# Generated by FakeRAM 2.0
VERSION 5.7 ;
BUSBITCHARS "[]" ;
PROPERTYDEFINITIONS
  MACRO width INTEGER ;
  MACRO depth INTEGER ;
  MACRO banks INTEGER ;
END PROPERTYDEFINITIONS
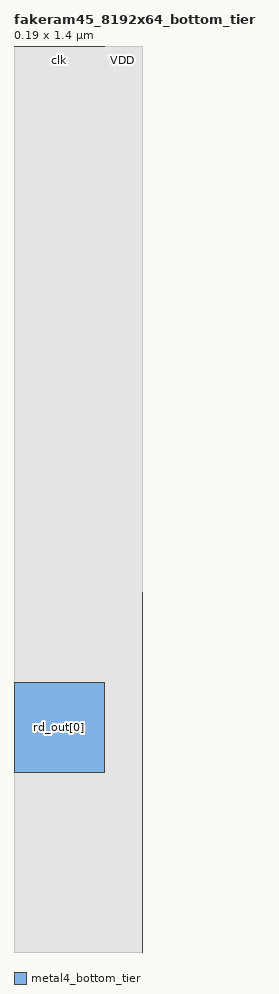
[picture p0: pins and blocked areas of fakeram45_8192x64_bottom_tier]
MACRO fakeram45_8192x64_bottom_tier
  PROPERTY width 64 ;
  PROPERTY depth 8192 ;
  PROPERTY banks 4 ;
  FOREIGN fakeram45_8192x64_bottom_tier 0 0 ;
  SYMMETRY X Y R90 ;
  SIZE 0.19 BY 1.4 ;
  CLASS BLOCK ;
  PIN rd_out[0]
    DIRECTION OUTPUT ;
    USE SIGNAL ;
    SHAPE ABUTMENT ;
    PORT
      LAYER metal4_bottom_tier ;
      RECT 0.000 0.280 0.140 0.420 ;
    END
  END rd_out[0]
  PIN rd_out[1]
    DIRECTION OUTPUT ;
    USE SIGNAL ;
    SHAPE ABUTMENT ;
    PORT
      LAYER metal4_bottom_tier ;
      RECT 0.000 6.160 0.140 6.300 ;
    END
  END rd_out[1]
  PIN rd_out[2]
    DIRECTION OUTPUT ;
    USE SIGNAL ;
    SHAPE ABUTMENT ;
    PORT
      LAYER metal4_bottom_tier ;
      RECT 0.000 12.040 0.140 12.180 ;
    END
  END rd_out[2]
  PIN rd_out[3]
    DIRECTION OUTPUT ;
    USE SIGNAL ;
    SHAPE ABUTMENT ;
    PORT
      LAYER metal4_bottom_tier ;
      RECT 0.000 17.920 0.140 18.060 ;
    END
  END rd_out[3]
  PIN rd_out[4]
    DIRECTION OUTPUT ;
    USE SIGNAL ;
    SHAPE ABUTMENT ;
    PORT
      LAYER metal4_bottom_tier ;
      RECT 0.000 23.800 0.140 23.940 ;
    END
  END rd_out[4]
  PIN rd_out[5]
    DIRECTION OUTPUT ;
    USE SIGNAL ;
    SHAPE ABUTMENT ;
    PORT
      LAYER metal4_bottom_tier ;
      RECT 0.000 29.680 0.140 29.820 ;
    END
  END rd_out[5]
  PIN rd_out[6]
    DIRECTION OUTPUT ;
    USE SIGNAL ;
    SHAPE ABUTMENT ;
    PORT
      LAYER metal4_bottom_tier ;
      RECT 0.000 35.560 0.140 35.700 ;
    END
  END rd_out[6]
  PIN rd_out[7]
    DIRECTION OUTPUT ;
    USE SIGNAL ;
    SHAPE ABUTMENT ;
    PORT
      LAYER metal4_bottom_tier ;
      RECT 0.000 41.440 0.140 41.580 ;
    END
  END rd_out[7]
  PIN rd_out[8]
    DIRECTION OUTPUT ;
    USE SIGNAL ;
    SHAPE ABUTMENT ;
    PORT
      LAYER metal4_bottom_tier ;
      RECT 0.000 47.320 0.140 47.460 ;
    END
  END rd_out[8]
  PIN rd_out[9]
    DIRECTION OUTPUT ;
    USE SIGNAL ;
    SHAPE ABUTMENT ;
    PORT
      LAYER metal4_bottom_tier ;
      RECT 0.000 53.200 0.140 53.340 ;
    END
  END rd_out[9]
  PIN rd_out[10]
    DIRECTION OUTPUT ;
    USE SIGNAL ;
    SHAPE ABUTMENT ;
    PORT
      LAYER metal4_bottom_tier ;
      RECT 0.000 59.080 0.140 59.220 ;
    END
  END rd_out[10]
  PIN rd_out[11]
    DIRECTION OUTPUT ;
    USE SIGNAL ;
    SHAPE ABUTMENT ;
    PORT
      LAYER metal4_bottom_tier ;
      RECT 0.000 64.960 0.140 65.100 ;
    END
  END rd_out[11]
  PIN rd_out[12]
    DIRECTION OUTPUT ;
    USE SIGNAL ;
    SHAPE ABUTMENT ;
    PORT
      LAYER metal4_bottom_tier ;
      RECT 0.000 70.840 0.140 70.980 ;
    END
  END rd_out[12]
  PIN rd_out[13]
    DIRECTION OUTPUT ;
    USE SIGNAL ;
    SHAPE ABUTMENT ;
    PORT
      LAYER metal4_bottom_tier ;
      RECT 0.000 76.720 0.140 76.860 ;
    END
  END rd_out[13]
  PIN rd_out[14]
    DIRECTION OUTPUT ;
    USE SIGNAL ;
    SHAPE ABUTMENT ;
    PORT
      LAYER metal4_bottom_tier ;
      RECT 0.000 82.600 0.140 82.740 ;
    END
  END rd_out[14]
  PIN rd_out[15]
    DIRECTION OUTPUT ;
    USE SIGNAL ;
    SHAPE ABUTMENT ;
    PORT
      LAYER metal4_bottom_tier ;
      RECT 0.000 88.480 0.140 88.620 ;
    END
  END rd_out[15]
  PIN rd_out[16]
    DIRECTION OUTPUT ;
    USE SIGNAL ;
    SHAPE ABUTMENT ;
    PORT
      LAYER metal4_bottom_tier ;
      RECT 0.000 94.360 0.140 94.500 ;
    END
  END rd_out[16]
  PIN rd_out[17]
    DIRECTION OUTPUT ;
    USE SIGNAL ;
    SHAPE ABUTMENT ;
    PORT
      LAYER metal4_bottom_tier ;
      RECT 0.000 100.240 0.140 100.380 ;
    END
  END rd_out[17]
  PIN rd_out[18]
    DIRECTION OUTPUT ;
    USE SIGNAL ;
    SHAPE ABUTMENT ;
    PORT
      LAYER metal4_bottom_tier ;
      RECT 0.000 106.120 0.140 106.260 ;
    END
  END rd_out[18]
  PIN rd_out[19]
    DIRECTION OUTPUT ;
    USE SIGNAL ;
    SHAPE ABUTMENT ;
    PORT
      LAYER metal4_bottom_tier ;
      RECT 0.000 112.000 0.140 112.140 ;
    END
  END rd_out[19]
  PIN rd_out[20]
    DIRECTION OUTPUT ;
    USE SIGNAL ;
    SHAPE ABUTMENT ;
    PORT
      LAYER metal4_bottom_tier ;
      RECT 0.000 117.880 0.140 118.020 ;
    END
  END rd_out[20]
  PIN rd_out[21]
    DIRECTION OUTPUT ;
    USE SIGNAL ;
    SHAPE ABUTMENT ;
    PORT
      LAYER metal4_bottom_tier ;
      RECT 0.000 123.760 0.140 123.900 ;
    END
  END rd_out[21]
  PIN rd_out[22]
    DIRECTION OUTPUT ;
    USE SIGNAL ;
    SHAPE ABUTMENT ;
    PORT
      LAYER metal4_bottom_tier ;
      RECT 0.000 129.640 0.140 129.780 ;
    END
  END rd_out[22]
  PIN rd_out[23]
    DIRECTION OUTPUT ;
    USE SIGNAL ;
    SHAPE ABUTMENT ;
    PORT
      LAYER metal4_bottom_tier ;
      RECT 0.000 135.520 0.140 135.660 ;
    END
  END rd_out[23]
  PIN rd_out[24]
    DIRECTION OUTPUT ;
    USE SIGNAL ;
    SHAPE ABUTMENT ;
    PORT
      LAYER metal4_bottom_tier ;
      RECT 0.000 141.400 0.140 141.540 ;
    END
  END rd_out[24]
  PIN rd_out[25]
    DIRECTION OUTPUT ;
    USE SIGNAL ;
    SHAPE ABUTMENT ;
    PORT
      LAYER metal4_bottom_tier ;
      RECT 0.000 147.280 0.140 147.420 ;
    END
  END rd_out[25]
  PIN rd_out[26]
    DIRECTION OUTPUT ;
    USE SIGNAL ;
    SHAPE ABUTMENT ;
    PORT
      LAYER metal4_bottom_tier ;
      RECT 0.000 153.160 0.140 153.300 ;
    END
  END rd_out[26]
  PIN rd_out[27]
    DIRECTION OUTPUT ;
    USE SIGNAL ;
    SHAPE ABUTMENT ;
    PORT
      LAYER metal4_bottom_tier ;
      RECT 0.000 159.040 0.140 159.180 ;
    END
  END rd_out[27]
  PIN rd_out[28]
    DIRECTION OUTPUT ;
    USE SIGNAL ;
    SHAPE ABUTMENT ;
    PORT
      LAYER metal4_bottom_tier ;
      RECT 0.000 164.920 0.140 165.060 ;
    END
  END rd_out[28]
  PIN rd_out[29]
    DIRECTION OUTPUT ;
    USE SIGNAL ;
    SHAPE ABUTMENT ;
    PORT
      LAYER metal4_bottom_tier ;
      RECT 0.000 170.800 0.140 170.940 ;
    END
  END rd_out[29]
  PIN rd_out[30]
    DIRECTION OUTPUT ;
    USE SIGNAL ;
    SHAPE ABUTMENT ;
    PORT
      LAYER metal4_bottom_tier ;
      RECT 0.000 176.680 0.140 176.820 ;
    END
  END rd_out[30]
  PIN rd_out[31]
    DIRECTION OUTPUT ;
    USE SIGNAL ;
    SHAPE ABUTMENT ;
    PORT
      LAYER metal4_bottom_tier ;
      RECT 0.000 182.560 0.140 182.700 ;
    END
  END rd_out[31]
  PIN rd_out[32]
    DIRECTION OUTPUT ;
    USE SIGNAL ;
    SHAPE ABUTMENT ;
    PORT
      LAYER metal4_bottom_tier ;
      RECT 0.000 188.440 0.140 188.580 ;
    END
  END rd_out[32]
  PIN rd_out[33]
    DIRECTION OUTPUT ;
    USE SIGNAL ;
    SHAPE ABUTMENT ;
    PORT
      LAYER metal4_bottom_tier ;
      RECT 0.000 194.320 0.140 194.460 ;
    END
  END rd_out[33]
  PIN rd_out[34]
    DIRECTION OUTPUT ;
    USE SIGNAL ;
    SHAPE ABUTMENT ;
    PORT
      LAYER metal4_bottom_tier ;
      RECT 0.000 200.200 0.140 200.340 ;
    END
  END rd_out[34]
  PIN rd_out[35]
    DIRECTION OUTPUT ;
    USE SIGNAL ;
    SHAPE ABUTMENT ;
    PORT
      LAYER metal4_bottom_tier ;
      RECT 0.000 206.080 0.140 206.220 ;
    END
  END rd_out[35]
  PIN rd_out[36]
    DIRECTION OUTPUT ;
    USE SIGNAL ;
    SHAPE ABUTMENT ;
    PORT
      LAYER metal4_bottom_tier ;
      RECT 0.000 211.960 0.140 212.100 ;
    END
  END rd_out[36]
  PIN rd_out[37]
    DIRECTION OUTPUT ;
    USE SIGNAL ;
    SHAPE ABUTMENT ;
    PORT
      LAYER metal4_bottom_tier ;
      RECT 0.000 217.840 0.140 217.980 ;
    END
  END rd_out[37]
  PIN rd_out[38]
    DIRECTION OUTPUT ;
    USE SIGNAL ;
    SHAPE ABUTMENT ;
    PORT
      LAYER metal4_bottom_tier ;
      RECT 0.000 223.720 0.140 223.860 ;
    END
  END rd_out[38]
  PIN rd_out[39]
    DIRECTION OUTPUT ;
    USE SIGNAL ;
    SHAPE ABUTMENT ;
    PORT
      LAYER metal4_bottom_tier ;
      RECT 0.000 229.600 0.140 229.740 ;
    END
  END rd_out[39]
  PIN rd_out[40]
    DIRECTION OUTPUT ;
    USE SIGNAL ;
    SHAPE ABUTMENT ;
    PORT
      LAYER metal4_bottom_tier ;
      RECT 0.000 235.480 0.140 235.620 ;
    END
  END rd_out[40]
  PIN rd_out[41]
    DIRECTION OUTPUT ;
    USE SIGNAL ;
    SHAPE ABUTMENT ;
    PORT
      LAYER metal4_bottom_tier ;
      RECT 0.000 241.360 0.140 241.500 ;
    END
  END rd_out[41]
  PIN rd_out[42]
    DIRECTION OUTPUT ;
    USE SIGNAL ;
    SHAPE ABUTMENT ;
    PORT
      LAYER metal4_bottom_tier ;
      RECT 0.000 247.240 0.140 247.380 ;
    END
  END rd_out[42]
  PIN rd_out[43]
    DIRECTION OUTPUT ;
    USE SIGNAL ;
    SHAPE ABUTMENT ;
    PORT
      LAYER metal4_bottom_tier ;
      RECT 0.000 253.120 0.140 253.260 ;
    END
  END rd_out[43]
  PIN rd_out[44]
    DIRECTION OUTPUT ;
    USE SIGNAL ;
    SHAPE ABUTMENT ;
    PORT
      LAYER metal4_bottom_tier ;
      RECT 0.000 259.000 0.140 259.140 ;
    END
  END rd_out[44]
  PIN rd_out[45]
    DIRECTION OUTPUT ;
    USE SIGNAL ;
    SHAPE ABUTMENT ;
    PORT
      LAYER metal4_bottom_tier ;
      RECT 0.000 264.880 0.140 265.020 ;
    END
  END rd_out[45]
  PIN rd_out[46]
    DIRECTION OUTPUT ;
    USE SIGNAL ;
    SHAPE ABUTMENT ;
    PORT
      LAYER metal4_bottom_tier ;
      RECT 0.000 270.760 0.140 270.900 ;
    END
  END rd_out[46]
  PIN rd_out[47]
    DIRECTION OUTPUT ;
    USE SIGNAL ;
    SHAPE ABUTMENT ;
    PORT
      LAYER metal4_bottom_tier ;
      RECT 0.000 276.640 0.140 276.780 ;
    END
  END rd_out[47]
  PIN rd_out[48]
    DIRECTION OUTPUT ;
    USE SIGNAL ;
    SHAPE ABUTMENT ;
    PORT
      LAYER metal4_bottom_tier ;
      RECT 0.000 282.520 0.140 282.660 ;
    END
  END rd_out[48]
  PIN rd_out[49]
    DIRECTION OUTPUT ;
    USE SIGNAL ;
    SHAPE ABUTMENT ;
    PORT
      LAYER metal4_bottom_tier ;
      RECT 0.000 288.400 0.140 288.540 ;
    END
  END rd_out[49]
  PIN rd_out[50]
    DIRECTION OUTPUT ;
    USE SIGNAL ;
    SHAPE ABUTMENT ;
    PORT
      LAYER metal4_bottom_tier ;
      RECT 0.000 294.280 0.140 294.420 ;
    END
  END rd_out[50]
  PIN rd_out[51]
    DIRECTION OUTPUT ;
    USE SIGNAL ;
    SHAPE ABUTMENT ;
    PORT
      LAYER metal4_bottom_tier ;
      RECT 0.000 300.160 0.140 300.300 ;
    END
  END rd_out[51]
  PIN rd_out[52]
    DIRECTION OUTPUT ;
    USE SIGNAL ;
    SHAPE ABUTMENT ;
    PORT
      LAYER metal4_bottom_tier ;
      RECT 0.000 306.040 0.140 306.180 ;
    END
  END rd_out[52]
  PIN rd_out[53]
    DIRECTION OUTPUT ;
    USE SIGNAL ;
    SHAPE ABUTMENT ;
    PORT
      LAYER metal4_bottom_tier ;
      RECT 0.000 311.920 0.140 312.060 ;
    END
  END rd_out[53]
  PIN rd_out[54]
    DIRECTION OUTPUT ;
    USE SIGNAL ;
    SHAPE ABUTMENT ;
    PORT
      LAYER metal4_bottom_tier ;
      RECT 0.000 317.800 0.140 317.940 ;
    END
  END rd_out[54]
  PIN rd_out[55]
    DIRECTION OUTPUT ;
    USE SIGNAL ;
    SHAPE ABUTMENT ;
    PORT
      LAYER metal4_bottom_tier ;
      RECT 0.000 323.680 0.140 323.820 ;
    END
  END rd_out[55]
  PIN rd_out[56]
    DIRECTION OUTPUT ;
    USE SIGNAL ;
    SHAPE ABUTMENT ;
    PORT
      LAYER metal4_bottom_tier ;
      RECT 0.000 329.560 0.140 329.700 ;
    END
  END rd_out[56]
  PIN rd_out[57]
    DIRECTION OUTPUT ;
    USE SIGNAL ;
    SHAPE ABUTMENT ;
    PORT
      LAYER metal4_bottom_tier ;
      RECT 0.000 335.440 0.140 335.580 ;
    END
  END rd_out[57]
  PIN rd_out[58]
    DIRECTION OUTPUT ;
    USE SIGNAL ;
    SHAPE ABUTMENT ;
    PORT
      LAYER metal4_bottom_tier ;
      RECT 0.000 341.320 0.140 341.460 ;
    END
  END rd_out[58]
  PIN rd_out[59]
    DIRECTION OUTPUT ;
    USE SIGNAL ;
    SHAPE ABUTMENT ;
    PORT
      LAYER metal4_bottom_tier ;
      RECT 0.000 347.200 0.140 347.340 ;
    END
  END rd_out[59]
  PIN rd_out[60]
    DIRECTION OUTPUT ;
    USE SIGNAL ;
    SHAPE ABUTMENT ;
    PORT
      LAYER metal4_bottom_tier ;
      RECT 0.000 353.080 0.140 353.220 ;
    END
  END rd_out[60]
  PIN rd_out[61]
    DIRECTION OUTPUT ;
    USE SIGNAL ;
    SHAPE ABUTMENT ;
    PORT
      LAYER metal4_bottom_tier ;
      RECT 0.000 358.960 0.140 359.100 ;
    END
  END rd_out[61]
  PIN rd_out[62]
    DIRECTION OUTPUT ;
    USE SIGNAL ;
    SHAPE ABUTMENT ;
    PORT
      LAYER metal4_bottom_tier ;
      RECT 0.000 364.840 0.140 364.980 ;
    END
  END rd_out[62]
  PIN rd_out[63]
    DIRECTION OUTPUT ;
    USE SIGNAL ;
    SHAPE ABUTMENT ;
    PORT
      LAYER metal4_bottom_tier ;
      RECT 0.000 370.720 0.140 370.860 ;
    END
  END rd_out[63]
  PIN wd_in[0]
    DIRECTION INPUT ;
    USE SIGNAL ;
    SHAPE ABUTMENT ;
    PORT
      LAYER metal4_bottom_tier ;
      RECT 0.000 378.280 0.140 378.420 ;
    END
  END wd_in[0]
  PIN wd_in[1]
    DIRECTION INPUT ;
    USE SIGNAL ;
    SHAPE ABUTMENT ;
    PORT
      LAYER metal4_bottom_tier ;
      RECT 0.000 384.160 0.140 384.300 ;
    END
  END wd_in[1]
  PIN wd_in[2]
    DIRECTION INPUT ;
    USE SIGNAL ;
    SHAPE ABUTMENT ;
    PORT
      LAYER metal4_bottom_tier ;
      RECT 0.000 390.040 0.140 390.180 ;
    END
  END wd_in[2]
  PIN wd_in[3]
    DIRECTION INPUT ;
    USE SIGNAL ;
    SHAPE ABUTMENT ;
    PORT
      LAYER metal4_bottom_tier ;
      RECT 0.000 395.920 0.140 396.060 ;
    END
  END wd_in[3]
  PIN wd_in[4]
    DIRECTION INPUT ;
    USE SIGNAL ;
    SHAPE ABUTMENT ;
    PORT
      LAYER metal4_bottom_tier ;
      RECT 0.000 401.800 0.140 401.940 ;
    END
  END wd_in[4]
  PIN wd_in[5]
    DIRECTION INPUT ;
    USE SIGNAL ;
    SHAPE ABUTMENT ;
    PORT
      LAYER metal4_bottom_tier ;
      RECT 0.000 407.680 0.140 407.820 ;
    END
  END wd_in[5]
  PIN wd_in[6]
    DIRECTION INPUT ;
    USE SIGNAL ;
    SHAPE ABUTMENT ;
    PORT
      LAYER metal4_bottom_tier ;
      RECT 0.000 413.560 0.140 413.700 ;
    END
  END wd_in[6]
  PIN wd_in[7]
    DIRECTION INPUT ;
    USE SIGNAL ;
    SHAPE ABUTMENT ;
    PORT
      LAYER metal4_bottom_tier ;
      RECT 0.000 419.440 0.140 419.580 ;
    END
  END wd_in[7]
  PIN wd_in[8]
    DIRECTION INPUT ;
    USE SIGNAL ;
    SHAPE ABUTMENT ;
    PORT
      LAYER metal4_bottom_tier ;
      RECT 0.000 425.320 0.140 425.460 ;
    END
  END wd_in[8]
  PIN wd_in[9]
    DIRECTION INPUT ;
    USE SIGNAL ;
    SHAPE ABUTMENT ;
    PORT
      LAYER metal4_bottom_tier ;
      RECT 0.000 431.200 0.140 431.340 ;
    END
  END wd_in[9]
  PIN wd_in[10]
    DIRECTION INPUT ;
    USE SIGNAL ;
    SHAPE ABUTMENT ;
    PORT
      LAYER metal4_bottom_tier ;
      RECT 0.000 437.080 0.140 437.220 ;
    END
  END wd_in[10]
  PIN wd_in[11]
    DIRECTION INPUT ;
    USE SIGNAL ;
    SHAPE ABUTMENT ;
    PORT
      LAYER metal4_bottom_tier ;
      RECT 0.000 442.960 0.140 443.100 ;
    END
  END wd_in[11]
  PIN wd_in[12]
    DIRECTION INPUT ;
    USE SIGNAL ;
    SHAPE ABUTMENT ;
    PORT
      LAYER metal4_bottom_tier ;
      RECT 0.000 448.840 0.140 448.980 ;
    END
  END wd_in[12]
  PIN wd_in[13]
    DIRECTION INPUT ;
    USE SIGNAL ;
    SHAPE ABUTMENT ;
    PORT
      LAYER metal4_bottom_tier ;
      RECT 0.000 454.720 0.140 454.860 ;
    END
  END wd_in[13]
  PIN wd_in[14]
    DIRECTION INPUT ;
    USE SIGNAL ;
    SHAPE ABUTMENT ;
    PORT
      LAYER metal4_bottom_tier ;
      RECT 0.000 460.600 0.140 460.740 ;
    END
  END wd_in[14]
  PIN wd_in[15]
    DIRECTION INPUT ;
    USE SIGNAL ;
    SHAPE ABUTMENT ;
    PORT
      LAYER metal4_bottom_tier ;
      RECT 0.000 466.480 0.140 466.620 ;
    END
  END wd_in[15]
  PIN wd_in[16]
    DIRECTION INPUT ;
    USE SIGNAL ;
    SHAPE ABUTMENT ;
    PORT
      LAYER metal4_bottom_tier ;
      RECT 0.000 472.360 0.140 472.500 ;
    END
  END wd_in[16]
  PIN wd_in[17]
    DIRECTION INPUT ;
    USE SIGNAL ;
    SHAPE ABUTMENT ;
    PORT
      LAYER metal4_bottom_tier ;
      RECT 0.000 478.240 0.140 478.380 ;
    END
  END wd_in[17]
  PIN wd_in[18]
    DIRECTION INPUT ;
    USE SIGNAL ;
    SHAPE ABUTMENT ;
    PORT
      LAYER metal4_bottom_tier ;
      RECT 0.000 484.120 0.140 484.260 ;
    END
  END wd_in[18]
  PIN wd_in[19]
    DIRECTION INPUT ;
    USE SIGNAL ;
    SHAPE ABUTMENT ;
    PORT
      LAYER metal4_bottom_tier ;
      RECT 0.000 490.000 0.140 490.140 ;
    END
  END wd_in[19]
  PIN wd_in[20]
    DIRECTION INPUT ;
    USE SIGNAL ;
    SHAPE ABUTMENT ;
    PORT
      LAYER metal4_bottom_tier ;
      RECT 0.000 495.880 0.140 496.020 ;
    END
  END wd_in[20]
  PIN wd_in[21]
    DIRECTION INPUT ;
    USE SIGNAL ;
    SHAPE ABUTMENT ;
    PORT
      LAYER metal4_bottom_tier ;
      RECT 0.000 501.760 0.140 501.900 ;
    END
  END wd_in[21]
  PIN wd_in[22]
    DIRECTION INPUT ;
    USE SIGNAL ;
    SHAPE ABUTMENT ;
    PORT
      LAYER metal4_bottom_tier ;
      RECT 0.000 507.640 0.140 507.780 ;
    END
  END wd_in[22]
  PIN wd_in[23]
    DIRECTION INPUT ;
    USE SIGNAL ;
    SHAPE ABUTMENT ;
    PORT
      LAYER metal4_bottom_tier ;
      RECT 0.000 513.520 0.140 513.660 ;
    END
  END wd_in[23]
  PIN wd_in[24]
    DIRECTION INPUT ;
    USE SIGNAL ;
    SHAPE ABUTMENT ;
    PORT
      LAYER metal4_bottom_tier ;
      RECT 0.000 519.400 0.140 519.540 ;
    END
  END wd_in[24]
  PIN wd_in[25]
    DIRECTION INPUT ;
    USE SIGNAL ;
    SHAPE ABUTMENT ;
    PORT
      LAYER metal4_bottom_tier ;
      RECT 0.000 525.280 0.140 525.420 ;
    END
  END wd_in[25]
  PIN wd_in[26]
    DIRECTION INPUT ;
    USE SIGNAL ;
    SHAPE ABUTMENT ;
    PORT
      LAYER metal4_bottom_tier ;
      RECT 0.000 531.160 0.140 531.300 ;
    END
  END wd_in[26]
  PIN wd_in[27]
    DIRECTION INPUT ;
    USE SIGNAL ;
    SHAPE ABUTMENT ;
    PORT
      LAYER metal4_bottom_tier ;
      RECT 0.000 537.040 0.140 537.180 ;
    END
  END wd_in[27]
  PIN wd_in[28]
    DIRECTION INPUT ;
    USE SIGNAL ;
    SHAPE ABUTMENT ;
    PORT
      LAYER metal4_bottom_tier ;
      RECT 0.000 542.920 0.140 543.060 ;
    END
  END wd_in[28]
  PIN wd_in[29]
    DIRECTION INPUT ;
    USE SIGNAL ;
    SHAPE ABUTMENT ;
    PORT
      LAYER metal4_bottom_tier ;
      RECT 0.000 548.800 0.140 548.940 ;
    END
  END wd_in[29]
  PIN wd_in[30]
    DIRECTION INPUT ;
    USE SIGNAL ;
    SHAPE ABUTMENT ;
    PORT
      LAYER metal4_bottom_tier ;
      RECT 0.000 554.680 0.140 554.820 ;
    END
  END wd_in[30]
  PIN wd_in[31]
    DIRECTION INPUT ;
    USE SIGNAL ;
    SHAPE ABUTMENT ;
    PORT
      LAYER metal4_bottom_tier ;
      RECT 0.000 560.560 0.140 560.700 ;
    END
  END wd_in[31]
  PIN wd_in[32]
    DIRECTION INPUT ;
    USE SIGNAL ;
    SHAPE ABUTMENT ;
    PORT
      LAYER metal4_bottom_tier ;
      RECT 0.000 566.440 0.140 566.580 ;
    END
  END wd_in[32]
  PIN wd_in[33]
    DIRECTION INPUT ;
    USE SIGNAL ;
    SHAPE ABUTMENT ;
    PORT
      LAYER metal4_bottom_tier ;
      RECT 0.000 572.320 0.140 572.460 ;
    END
  END wd_in[33]
  PIN wd_in[34]
    DIRECTION INPUT ;
    USE SIGNAL ;
    SHAPE ABUTMENT ;
    PORT
      LAYER metal4_bottom_tier ;
      RECT 0.000 578.200 0.140 578.340 ;
    END
  END wd_in[34]
  PIN wd_in[35]
    DIRECTION INPUT ;
    USE SIGNAL ;
    SHAPE ABUTMENT ;
    PORT
      LAYER metal4_bottom_tier ;
      RECT 0.000 584.080 0.140 584.220 ;
    END
  END wd_in[35]
  PIN wd_in[36]
    DIRECTION INPUT ;
    USE SIGNAL ;
    SHAPE ABUTMENT ;
    PORT
      LAYER metal4_bottom_tier ;
      RECT 0.000 589.960 0.140 590.100 ;
    END
  END wd_in[36]
  PIN wd_in[37]
    DIRECTION INPUT ;
    USE SIGNAL ;
    SHAPE ABUTMENT ;
    PORT
      LAYER metal4_bottom_tier ;
      RECT 0.000 595.840 0.140 595.980 ;
    END
  END wd_in[37]
  PIN wd_in[38]
    DIRECTION INPUT ;
    USE SIGNAL ;
    SHAPE ABUTMENT ;
    PORT
      LAYER metal4_bottom_tier ;
      RECT 0.000 601.720 0.140 601.860 ;
    END
  END wd_in[38]
  PIN wd_in[39]
    DIRECTION INPUT ;
    USE SIGNAL ;
    SHAPE ABUTMENT ;
    PORT
      LAYER metal4_bottom_tier ;
      RECT 0.000 607.600 0.140 607.740 ;
    END
  END wd_in[39]
  PIN wd_in[40]
    DIRECTION INPUT ;
    USE SIGNAL ;
    SHAPE ABUTMENT ;
    PORT
      LAYER metal4_bottom_tier ;
      RECT 0.000 613.480 0.140 613.620 ;
    END
  END wd_in[40]
  PIN wd_in[41]
    DIRECTION INPUT ;
    USE SIGNAL ;
    SHAPE ABUTMENT ;
    PORT
      LAYER metal4_bottom_tier ;
      RECT 0.000 619.360 0.140 619.500 ;
    END
  END wd_in[41]
  PIN wd_in[42]
    DIRECTION INPUT ;
    USE SIGNAL ;
    SHAPE ABUTMENT ;
    PORT
      LAYER metal4_bottom_tier ;
      RECT 0.000 625.240 0.140 625.380 ;
    END
  END wd_in[42]
  PIN wd_in[43]
    DIRECTION INPUT ;
    USE SIGNAL ;
    SHAPE ABUTMENT ;
    PORT
      LAYER metal4_bottom_tier ;
      RECT 0.000 631.120 0.140 631.260 ;
    END
  END wd_in[43]
  PIN wd_in[44]
    DIRECTION INPUT ;
    USE SIGNAL ;
    SHAPE ABUTMENT ;
    PORT
      LAYER metal4_bottom_tier ;
      RECT 0.000 637.000 0.140 637.140 ;
    END
  END wd_in[44]
  PIN wd_in[45]
    DIRECTION INPUT ;
    USE SIGNAL ;
    SHAPE ABUTMENT ;
    PORT
      LAYER metal4_bottom_tier ;
      RECT 0.000 642.880 0.140 643.020 ;
    END
  END wd_in[45]
  PIN wd_in[46]
    DIRECTION INPUT ;
    USE SIGNAL ;
    SHAPE ABUTMENT ;
    PORT
      LAYER metal4_bottom_tier ;
      RECT 0.000 648.760 0.140 648.900 ;
    END
  END wd_in[46]
  PIN wd_in[47]
    DIRECTION INPUT ;
    USE SIGNAL ;
    SHAPE ABUTMENT ;
    PORT
      LAYER metal4_bottom_tier ;
      RECT 0.000 654.640 0.140 654.780 ;
    END
  END wd_in[47]
  PIN wd_in[48]
    DIRECTION INPUT ;
    USE SIGNAL ;
    SHAPE ABUTMENT ;
    PORT
      LAYER metal4_bottom_tier ;
      RECT 0.000 660.520 0.140 660.660 ;
    END
  END wd_in[48]
  PIN wd_in[49]
    DIRECTION INPUT ;
    USE SIGNAL ;
    SHAPE ABUTMENT ;
    PORT
      LAYER metal4_bottom_tier ;
      RECT 0.000 666.400 0.140 666.540 ;
    END
  END wd_in[49]
  PIN wd_in[50]
    DIRECTION INPUT ;
    USE SIGNAL ;
    SHAPE ABUTMENT ;
    PORT
      LAYER metal4_bottom_tier ;
      RECT 0.000 672.280 0.140 672.420 ;
    END
  END wd_in[50]
  PIN wd_in[51]
    DIRECTION INPUT ;
    USE SIGNAL ;
    SHAPE ABUTMENT ;
    PORT
      LAYER metal4_bottom_tier ;
      RECT 0.000 678.160 0.140 678.300 ;
    END
  END wd_in[51]
  PIN wd_in[52]
    DIRECTION INPUT ;
    USE SIGNAL ;
    SHAPE ABUTMENT ;
    PORT
      LAYER metal4_bottom_tier ;
      RECT 0.000 684.040 0.140 684.180 ;
    END
  END wd_in[52]
  PIN wd_in[53]
    DIRECTION INPUT ;
    USE SIGNAL ;
    SHAPE ABUTMENT ;
    PORT
      LAYER metal4_bottom_tier ;
      RECT 0.000 689.920 0.140 690.060 ;
    END
  END wd_in[53]
  PIN wd_in[54]
    DIRECTION INPUT ;
    USE SIGNAL ;
    SHAPE ABUTMENT ;
    PORT
      LAYER metal4_bottom_tier ;
      RECT 0.000 695.800 0.140 695.940 ;
    END
  END wd_in[54]
  PIN wd_in[55]
    DIRECTION INPUT ;
    USE SIGNAL ;
    SHAPE ABUTMENT ;
    PORT
      LAYER metal4_bottom_tier ;
      RECT 0.000 701.680 0.140 701.820 ;
    END
  END wd_in[55]
  PIN wd_in[56]
    DIRECTION INPUT ;
    USE SIGNAL ;
    SHAPE ABUTMENT ;
    PORT
      LAYER metal4_bottom_tier ;
      RECT 0.000 707.560 0.140 707.700 ;
    END
  END wd_in[56]
  PIN wd_in[57]
    DIRECTION INPUT ;
    USE SIGNAL ;
    SHAPE ABUTMENT ;
    PORT
      LAYER metal4_bottom_tier ;
      RECT 0.000 713.440 0.140 713.580 ;
    END
  END wd_in[57]
  PIN wd_in[58]
    DIRECTION INPUT ;
    USE SIGNAL ;
    SHAPE ABUTMENT ;
    PORT
      LAYER metal4_bottom_tier ;
      RECT 0.000 719.320 0.140 719.460 ;
    END
  END wd_in[58]
  PIN wd_in[59]
    DIRECTION INPUT ;
    USE SIGNAL ;
    SHAPE ABUTMENT ;
    PORT
      LAYER metal4_bottom_tier ;
      RECT 0.000 725.200 0.140 725.340 ;
    END
  END wd_in[59]
  PIN wd_in[60]
    DIRECTION INPUT ;
    USE SIGNAL ;
    SHAPE ABUTMENT ;
    PORT
      LAYER metal4_bottom_tier ;
      RECT 0.000 731.080 0.140 731.220 ;
    END
  END wd_in[60]
  PIN wd_in[61]
    DIRECTION INPUT ;
    USE SIGNAL ;
    SHAPE ABUTMENT ;
    PORT
      LAYER metal4_bottom_tier ;
      RECT 0.000 736.960 0.140 737.100 ;
    END
  END wd_in[61]
  PIN wd_in[62]
    DIRECTION INPUT ;
    USE SIGNAL ;
    SHAPE ABUTMENT ;
    PORT
      LAYER metal4_bottom_tier ;
      RECT 0.000 742.840 0.140 742.980 ;
    END
  END wd_in[62]
  PIN wd_in[63]
    DIRECTION INPUT ;
    USE SIGNAL ;
    SHAPE ABUTMENT ;
    PORT
      LAYER metal4_bottom_tier ;
      RECT 0.000 748.720 0.140 748.860 ;
    END
  END wd_in[63]
  PIN addr_in[0]
    DIRECTION INPUT ;
    USE SIGNAL ;
    SHAPE ABUTMENT ;
    PORT
      LAYER metal4_bottom_tier ;
      RECT 0.000 756.280 0.140 756.420 ;
    END
  END addr_in[0]
  PIN addr_in[1]
    DIRECTION INPUT ;
    USE SIGNAL ;
    SHAPE ABUTMENT ;
    PORT
      LAYER metal4_bottom_tier ;
      RECT 0.000 762.160 0.140 762.300 ;
    END
  END addr_in[1]
  PIN addr_in[2]
    DIRECTION INPUT ;
    USE SIGNAL ;
    SHAPE ABUTMENT ;
    PORT
      LAYER metal4_bottom_tier ;
      RECT 0.000 768.040 0.140 768.180 ;
    END
  END addr_in[2]
  PIN addr_in[3]
    DIRECTION INPUT ;
    USE SIGNAL ;
    SHAPE ABUTMENT ;
    PORT
      LAYER metal4_bottom_tier ;
      RECT 0.000 773.920 0.140 774.060 ;
    END
  END addr_in[3]
  PIN addr_in[4]
    DIRECTION INPUT ;
    USE SIGNAL ;
    SHAPE ABUTMENT ;
    PORT
      LAYER metal4_bottom_tier ;
      RECT 0.000 779.800 0.140 779.940 ;
    END
  END addr_in[4]
  PIN addr_in[5]
    DIRECTION INPUT ;
    USE SIGNAL ;
    SHAPE ABUTMENT ;
    PORT
      LAYER metal4_bottom_tier ;
      RECT 0.000 785.680 0.140 785.820 ;
    END
  END addr_in[5]
  PIN addr_in[6]
    DIRECTION INPUT ;
    USE SIGNAL ;
    SHAPE ABUTMENT ;
    PORT
      LAYER metal4_bottom_tier ;
      RECT 0.000 791.560 0.140 791.700 ;
    END
  END addr_in[6]
  PIN addr_in[7]
    DIRECTION INPUT ;
    USE SIGNAL ;
    SHAPE ABUTMENT ;
    PORT
      LAYER metal4_bottom_tier ;
      RECT 0.000 797.440 0.140 797.580 ;
    END
  END addr_in[7]
  PIN addr_in[8]
    DIRECTION INPUT ;
    USE SIGNAL ;
    SHAPE ABUTMENT ;
    PORT
      LAYER metal4_bottom_tier ;
      RECT 0.000 803.320 0.140 803.460 ;
    END
  END addr_in[8]
  PIN addr_in[9]
    DIRECTION INPUT ;
    USE SIGNAL ;
    SHAPE ABUTMENT ;
    PORT
      LAYER metal4_bottom_tier ;
      RECT 0.000 809.200 0.140 809.340 ;
    END
  END addr_in[9]
  PIN addr_in[10]
    DIRECTION INPUT ;
    USE SIGNAL ;
    SHAPE ABUTMENT ;
    PORT
      LAYER metal4_bottom_tier ;
      RECT 0.000 815.080 0.140 815.220 ;
    END
  END addr_in[10]
  PIN addr_in[11]
    DIRECTION INPUT ;
    USE SIGNAL ;
    SHAPE ABUTMENT ;
    PORT
      LAYER metal4_bottom_tier ;
      RECT 0.000 820.960 0.140 821.100 ;
    END
  END addr_in[11]
  PIN addr_in[12]
    DIRECTION INPUT ;
    USE SIGNAL ;
    SHAPE ABUTMENT ;
    PORT
      LAYER metal4_bottom_tier ;
      RECT 0.000 826.840 0.140 826.980 ;
    END
  END addr_in[12]
  PIN w_mask_in[0]
    DIRECTION OUTPUT ;
    USE SIGNAL ;
    SHAPE ABUTMENT ;
    PORT
      LAYER metal4_bottom_tier ;
      RECT 0.000 834.400 0.140 834.540 ;
    END
  END w_mask_in[0]
  PIN w_mask_in[1]
    DIRECTION OUTPUT ;
    USE SIGNAL ;
    SHAPE ABUTMENT ;
    PORT
      LAYER metal4_bottom_tier ;
      RECT 0.000 840.280 0.140 840.420 ;
    END
  END w_mask_in[1]
  PIN w_mask_in[2]
    DIRECTION OUTPUT ;
    USE SIGNAL ;
    SHAPE ABUTMENT ;
    PORT
      LAYER metal4_bottom_tier ;
      RECT 0.000 846.160 0.140 846.300 ;
    END
  END w_mask_in[2]
  PIN w_mask_in[3]
    DIRECTION OUTPUT ;
    USE SIGNAL ;
    SHAPE ABUTMENT ;
    PORT
      LAYER metal4_bottom_tier ;
      RECT 0.000 852.040 0.140 852.180 ;
    END
  END w_mask_in[3]
  PIN w_mask_in[4]
    DIRECTION OUTPUT ;
    USE SIGNAL ;
    SHAPE ABUTMENT ;
    PORT
      LAYER metal4_bottom_tier ;
      RECT 0.000 857.920 0.140 858.060 ;
    END
  END w_mask_in[4]
  PIN w_mask_in[5]
    DIRECTION OUTPUT ;
    USE SIGNAL ;
    SHAPE ABUTMENT ;
    PORT
      LAYER metal4_bottom_tier ;
      RECT 0.000 863.800 0.140 863.940 ;
    END
  END w_mask_in[5]
  PIN w_mask_in[6]
    DIRECTION OUTPUT ;
    USE SIGNAL ;
    SHAPE ABUTMENT ;
    PORT
      LAYER metal4_bottom_tier ;
      RECT 0.000 869.680 0.140 869.820 ;
    END
  END w_mask_in[6]
  PIN w_mask_in[7]
    DIRECTION OUTPUT ;
    USE SIGNAL ;
    SHAPE ABUTMENT ;
    PORT
      LAYER metal4_bottom_tier ;
      RECT 0.000 875.560 0.140 875.700 ;
    END
  END w_mask_in[7]
  PIN w_mask_in[8]
    DIRECTION OUTPUT ;
    USE SIGNAL ;
    SHAPE ABUTMENT ;
    PORT
      LAYER metal4_bottom_tier ;
      RECT 0.000 881.440 0.140 881.580 ;
    END
  END w_mask_in[8]
  PIN w_mask_in[9]
    DIRECTION OUTPUT ;
    USE SIGNAL ;
    SHAPE ABUTMENT ;
    PORT
      LAYER metal4_bottom_tier ;
      RECT 0.000 887.320 0.140 887.460 ;
    END
  END w_mask_in[9]
  PIN w_mask_in[10]
    DIRECTION OUTPUT ;
    USE SIGNAL ;
    SHAPE ABUTMENT ;
    PORT
      LAYER metal4_bottom_tier ;
      RECT 0.000 893.200 0.140 893.340 ;
    END
  END w_mask_in[10]
  PIN w_mask_in[11]
    DIRECTION OUTPUT ;
    USE SIGNAL ;
    SHAPE ABUTMENT ;
    PORT
      LAYER metal4_bottom_tier ;
      RECT 0.000 899.080 0.140 899.220 ;
    END
  END w_mask_in[11]
  PIN w_mask_in[12]
    DIRECTION OUTPUT ;
    USE SIGNAL ;
    SHAPE ABUTMENT ;
    PORT
      LAYER metal4_bottom_tier ;
      RECT 0.000 904.960 0.140 905.100 ;
    END
  END w_mask_in[12]
  PIN w_mask_in[13]
    DIRECTION OUTPUT ;
    USE SIGNAL ;
    SHAPE ABUTMENT ;
    PORT
      LAYER metal4_bottom_tier ;
      RECT 0.000 910.840 0.140 910.980 ;
    END
  END w_mask_in[13]
  PIN w_mask_in[14]
    DIRECTION OUTPUT ;
    USE SIGNAL ;
    SHAPE ABUTMENT ;
    PORT
      LAYER metal4_bottom_tier ;
      RECT 0.000 916.720 0.140 916.860 ;
    END
  END w_mask_in[14]
  PIN w_mask_in[15]
    DIRECTION OUTPUT ;
    USE SIGNAL ;
    SHAPE ABUTMENT ;
    PORT
      LAYER metal4_bottom_tier ;
      RECT 0.000 922.600 0.140 922.740 ;
    END
  END w_mask_in[15]
  PIN w_mask_in[16]
    DIRECTION OUTPUT ;
    USE SIGNAL ;
    SHAPE ABUTMENT ;
    PORT
      LAYER metal4_bottom_tier ;
      RECT 0.000 928.480 0.140 928.620 ;
    END
  END w_mask_in[16]
  PIN w_mask_in[17]
    DIRECTION OUTPUT ;
    USE SIGNAL ;
    SHAPE ABUTMENT ;
    PORT
      LAYER metal4_bottom_tier ;
      RECT 0.000 934.360 0.140 934.500 ;
    END
  END w_mask_in[17]
  PIN w_mask_in[18]
    DIRECTION OUTPUT ;
    USE SIGNAL ;
    SHAPE ABUTMENT ;
    PORT
      LAYER metal4_bottom_tier ;
      RECT 0.000 940.240 0.140 940.380 ;
    END
  END w_mask_in[18]
  PIN w_mask_in[19]
    DIRECTION OUTPUT ;
    USE SIGNAL ;
    SHAPE ABUTMENT ;
    PORT
      LAYER metal4_bottom_tier ;
      RECT 0.000 946.120 0.140 946.260 ;
    END
  END w_mask_in[19]
  PIN w_mask_in[20]
    DIRECTION OUTPUT ;
    USE SIGNAL ;
    SHAPE ABUTMENT ;
    PORT
      LAYER metal4_bottom_tier ;
      RECT 0.000 952.000 0.140 952.140 ;
    END
  END w_mask_in[20]
  PIN w_mask_in[21]
    DIRECTION OUTPUT ;
    USE SIGNAL ;
    SHAPE ABUTMENT ;
    PORT
      LAYER metal4_bottom_tier ;
      RECT 0.000 957.880 0.140 958.020 ;
    END
  END w_mask_in[21]
  PIN w_mask_in[22]
    DIRECTION OUTPUT ;
    USE SIGNAL ;
    SHAPE ABUTMENT ;
    PORT
      LAYER metal4_bottom_tier ;
      RECT 0.000 963.760 0.140 963.900 ;
    END
  END w_mask_in[22]
  PIN w_mask_in[23]
    DIRECTION OUTPUT ;
    USE SIGNAL ;
    SHAPE ABUTMENT ;
    PORT
      LAYER metal4_bottom_tier ;
      RECT 0.000 969.640 0.140 969.780 ;
    END
  END w_mask_in[23]
  PIN w_mask_in[24]
    DIRECTION OUTPUT ;
    USE SIGNAL ;
    SHAPE ABUTMENT ;
    PORT
      LAYER metal4_bottom_tier ;
      RECT 0.000 975.520 0.140 975.660 ;
    END
  END w_mask_in[24]
  PIN w_mask_in[25]
    DIRECTION OUTPUT ;
    USE SIGNAL ;
    SHAPE ABUTMENT ;
    PORT
      LAYER metal4_bottom_tier ;
      RECT 0.000 981.400 0.140 981.540 ;
    END
  END w_mask_in[25]
  PIN w_mask_in[26]
    DIRECTION OUTPUT ;
    USE SIGNAL ;
    SHAPE ABUTMENT ;
    PORT
      LAYER metal4_bottom_tier ;
      RECT 0.000 987.280 0.140 987.420 ;
    END
  END w_mask_in[26]
  PIN w_mask_in[27]
    DIRECTION OUTPUT ;
    USE SIGNAL ;
    SHAPE ABUTMENT ;
    PORT
      LAYER metal4_bottom_tier ;
      RECT 0.000 993.160 0.140 993.300 ;
    END
  END w_mask_in[27]
  PIN w_mask_in[28]
    DIRECTION OUTPUT ;
    USE SIGNAL ;
    SHAPE ABUTMENT ;
    PORT
      LAYER metal4_bottom_tier ;
      RECT 0.000 999.040 0.140 999.180 ;
    END
  END w_mask_in[28]
  PIN w_mask_in[29]
    DIRECTION OUTPUT ;
    USE SIGNAL ;
    SHAPE ABUTMENT ;
    PORT
      LAYER metal4_bottom_tier ;
      RECT 0.000 1004.920 0.140 1005.060 ;
    END
  END w_mask_in[29]
  PIN w_mask_in[30]
    DIRECTION OUTPUT ;
    USE SIGNAL ;
    SHAPE ABUTMENT ;
    PORT
      LAYER metal4_bottom_tier ;
      RECT 0.000 1010.800 0.140 1010.940 ;
    END
  END w_mask_in[30]
  PIN w_mask_in[31]
    DIRECTION OUTPUT ;
    USE SIGNAL ;
    SHAPE ABUTMENT ;
    PORT
      LAYER metal4_bottom_tier ;
      RECT 0.000 1016.680 0.140 1016.820 ;
    END
  END w_mask_in[31]
  PIN w_mask_in[32]
    DIRECTION OUTPUT ;
    USE SIGNAL ;
    SHAPE ABUTMENT ;
    PORT
      LAYER metal4_bottom_tier ;
      RECT 0.000 1022.560 0.140 1022.700 ;
    END
  END w_mask_in[32]
  PIN w_mask_in[33]
    DIRECTION OUTPUT ;
    USE SIGNAL ;
    SHAPE ABUTMENT ;
    PORT
      LAYER metal4_bottom_tier ;
      RECT 0.000 1028.440 0.140 1028.580 ;
    END
  END w_mask_in[33]
  PIN w_mask_in[34]
    DIRECTION OUTPUT ;
    USE SIGNAL ;
    SHAPE ABUTMENT ;
    PORT
      LAYER metal4_bottom_tier ;
      RECT 0.000 1034.320 0.140 1034.460 ;
    END
  END w_mask_in[34]
  PIN w_mask_in[35]
    DIRECTION OUTPUT ;
    USE SIGNAL ;
    SHAPE ABUTMENT ;
    PORT
      LAYER metal4_bottom_tier ;
      RECT 0.000 1040.200 0.140 1040.340 ;
    END
  END w_mask_in[35]
  PIN w_mask_in[36]
    DIRECTION OUTPUT ;
    USE SIGNAL ;
    SHAPE ABUTMENT ;
    PORT
      LAYER metal4_bottom_tier ;
      RECT 0.000 1046.080 0.140 1046.220 ;
    END
  END w_mask_in[36]
  PIN w_mask_in[37]
    DIRECTION OUTPUT ;
    USE SIGNAL ;
    SHAPE ABUTMENT ;
    PORT
      LAYER metal4_bottom_tier ;
      RECT 0.000 1051.960 0.140 1052.100 ;
    END
  END w_mask_in[37]
  PIN w_mask_in[38]
    DIRECTION OUTPUT ;
    USE SIGNAL ;
    SHAPE ABUTMENT ;
    PORT
      LAYER metal4_bottom_tier ;
      RECT 0.000 1057.840 0.140 1057.980 ;
    END
  END w_mask_in[38]
  PIN w_mask_in[39]
    DIRECTION OUTPUT ;
    USE SIGNAL ;
    SHAPE ABUTMENT ;
    PORT
      LAYER metal4_bottom_tier ;
      RECT 0.000 1063.720 0.140 1063.860 ;
    END
  END w_mask_in[39]
  PIN w_mask_in[40]
    DIRECTION OUTPUT ;
    USE SIGNAL ;
    SHAPE ABUTMENT ;
    PORT
      LAYER metal4_bottom_tier ;
      RECT 0.000 1069.600 0.140 1069.740 ;
    END
  END w_mask_in[40]
  PIN w_mask_in[41]
    DIRECTION OUTPUT ;
    USE SIGNAL ;
    SHAPE ABUTMENT ;
    PORT
      LAYER metal4_bottom_tier ;
      RECT 0.000 1075.480 0.140 1075.620 ;
    END
  END w_mask_in[41]
  PIN w_mask_in[42]
    DIRECTION OUTPUT ;
    USE SIGNAL ;
    SHAPE ABUTMENT ;
    PORT
      LAYER metal4_bottom_tier ;
      RECT 0.000 1081.360 0.140 1081.500 ;
    END
  END w_mask_in[42]
  PIN w_mask_in[43]
    DIRECTION OUTPUT ;
    USE SIGNAL ;
    SHAPE ABUTMENT ;
    PORT
      LAYER metal4_bottom_tier ;
      RECT 0.000 1087.240 0.140 1087.380 ;
    END
  END w_mask_in[43]
  PIN w_mask_in[44]
    DIRECTION OUTPUT ;
    USE SIGNAL ;
    SHAPE ABUTMENT ;
    PORT
      LAYER metal4_bottom_tier ;
      RECT 0.000 1093.120 0.140 1093.260 ;
    END
  END w_mask_in[44]
  PIN w_mask_in[45]
    DIRECTION OUTPUT ;
    USE SIGNAL ;
    SHAPE ABUTMENT ;
    PORT
      LAYER metal4_bottom_tier ;
      RECT 0.000 1099.000 0.140 1099.140 ;
    END
  END w_mask_in[45]
  PIN w_mask_in[46]
    DIRECTION OUTPUT ;
    USE SIGNAL ;
    SHAPE ABUTMENT ;
    PORT
      LAYER metal4_bottom_tier ;
      RECT 0.000 1104.880 0.140 1105.020 ;
    END
  END w_mask_in[46]
  PIN w_mask_in[47]
    DIRECTION OUTPUT ;
    USE SIGNAL ;
    SHAPE ABUTMENT ;
    PORT
      LAYER metal4_bottom_tier ;
      RECT 0.000 1110.760 0.140 1110.900 ;
    END
  END w_mask_in[47]
  PIN w_mask_in[48]
    DIRECTION OUTPUT ;
    USE SIGNAL ;
    SHAPE ABUTMENT ;
    PORT
      LAYER metal4_bottom_tier ;
      RECT 0.000 1116.640 0.140 1116.780 ;
    END
  END w_mask_in[48]
  PIN w_mask_in[49]
    DIRECTION OUTPUT ;
    USE SIGNAL ;
    SHAPE ABUTMENT ;
    PORT
      LAYER metal4_bottom_tier ;
      RECT 0.000 1122.520 0.140 1122.660 ;
    END
  END w_mask_in[49]
  PIN w_mask_in[50]
    DIRECTION OUTPUT ;
    USE SIGNAL ;
    SHAPE ABUTMENT ;
    PORT
      LAYER metal4_bottom_tier ;
      RECT 0.000 1128.400 0.140 1128.540 ;
    END
  END w_mask_in[50]
  PIN w_mask_in[51]
    DIRECTION OUTPUT ;
    USE SIGNAL ;
    SHAPE ABUTMENT ;
    PORT
      LAYER metal4_bottom_tier ;
      RECT 0.000 1134.280 0.140 1134.420 ;
    END
  END w_mask_in[51]
  PIN w_mask_in[52]
    DIRECTION OUTPUT ;
    USE SIGNAL ;
    SHAPE ABUTMENT ;
    PORT
      LAYER metal4_bottom_tier ;
      RECT 0.000 1140.160 0.140 1140.300 ;
    END
  END w_mask_in[52]
  PIN w_mask_in[53]
    DIRECTION OUTPUT ;
    USE SIGNAL ;
    SHAPE ABUTMENT ;
    PORT
      LAYER metal4_bottom_tier ;
      RECT 0.000 1146.040 0.140 1146.180 ;
    END
  END w_mask_in[53]
  PIN w_mask_in[54]
    DIRECTION OUTPUT ;
    USE SIGNAL ;
    SHAPE ABUTMENT ;
    PORT
      LAYER metal4_bottom_tier ;
      RECT 0.000 1151.920 0.140 1152.060 ;
    END
  END w_mask_in[54]
  PIN w_mask_in[55]
    DIRECTION OUTPUT ;
    USE SIGNAL ;
    SHAPE ABUTMENT ;
    PORT
      LAYER metal4_bottom_tier ;
      RECT 0.000 1157.800 0.140 1157.940 ;
    END
  END w_mask_in[55]
  PIN w_mask_in[56]
    DIRECTION OUTPUT ;
    USE SIGNAL ;
    SHAPE ABUTMENT ;
    PORT
      LAYER metal4_bottom_tier ;
      RECT 0.000 1163.680 0.140 1163.820 ;
    END
  END w_mask_in[56]
  PIN w_mask_in[57]
    DIRECTION OUTPUT ;
    USE SIGNAL ;
    SHAPE ABUTMENT ;
    PORT
      LAYER metal4_bottom_tier ;
      RECT 0.000 1169.560 0.140 1169.700 ;
    END
  END w_mask_in[57]
  PIN w_mask_in[58]
    DIRECTION OUTPUT ;
    USE SIGNAL ;
    SHAPE ABUTMENT ;
    PORT
      LAYER metal4_bottom_tier ;
      RECT 0.000 1175.440 0.140 1175.580 ;
    END
  END w_mask_in[58]
  PIN w_mask_in[59]
    DIRECTION OUTPUT ;
    USE SIGNAL ;
    SHAPE ABUTMENT ;
    PORT
      LAYER metal4_bottom_tier ;
      RECT 0.000 1181.320 0.140 1181.460 ;
    END
  END w_mask_in[59]
  PIN w_mask_in[60]
    DIRECTION OUTPUT ;
    USE SIGNAL ;
    SHAPE ABUTMENT ;
    PORT
      LAYER metal4_bottom_tier ;
      RECT 0.000 1187.200 0.140 1187.340 ;
    END
  END w_mask_in[60]
  PIN w_mask_in[61]
    DIRECTION OUTPUT ;
    USE SIGNAL ;
    SHAPE ABUTMENT ;
    PORT
      LAYER metal4_bottom_tier ;
      RECT 0.000 1193.080 0.140 1193.220 ;
    END
  END w_mask_in[61]
  PIN w_mask_in[62]
    DIRECTION OUTPUT ;
    USE SIGNAL ;
    SHAPE ABUTMENT ;
    PORT
      LAYER metal4_bottom_tier ;
      RECT 0.000 1198.960 0.140 1199.100 ;
    END
  END w_mask_in[62]
  PIN w_mask_in[63]
    DIRECTION OUTPUT ;
    USE SIGNAL ;
    SHAPE ABUTMENT ;
    PORT
      LAYER metal4_bottom_tier ;
      RECT 0.000 1204.840 0.140 1204.980 ;
    END
  END w_mask_in[63]
  PIN we_in
    DIRECTION INPUT ;
    USE SIGNAL ;
    SHAPE ABUTMENT ;
    PORT
      LAYER metal4_bottom_tier ;
      RECT 0.000 1212.400 0.140 1212.540 ;
    END
  END we_in
  PIN ce_in
    DIRECTION INPUT ;
    USE SIGNAL ;
    SHAPE ABUTMENT ;
    PORT
      LAYER metal4_bottom_tier ;
      RECT 0.000 1218.280 0.140 1218.420 ;
    END
  END ce_in
  PIN clk
    DIRECTION INPUT ;
    USE SIGNAL ;
    SHAPE ABUTMENT ;
    PORT
      LAYER metal4_bottom_tier ;
      RECT 0.000 1224.160 0.140 1224.300 ;
    END
  END clk
  PIN VSS
    DIRECTION INOUT ;
    USE GROUND ;
    PORT
      LAYER metal4_bottom_tier ;
      RECT 0.280 0.000 208.720 0.560 ;
      RECT 0.280 4.480 208.720 5.040 ;
      RECT 0.280 8.960 208.720 9.520 ;
      RECT 0.280 13.440 208.720 14.000 ;
      RECT 0.280 17.920 208.720 18.480 ;
      RECT 0.280 22.400 208.720 22.960 ;
      RECT 0.280 26.880 208.720 27.440 ;
      RECT 0.280 31.360 208.720 31.920 ;
      RECT 0.280 35.840 208.720 36.400 ;
      RECT 0.280 40.320 208.720 40.880 ;
      RECT 0.280 44.800 208.720 45.360 ;
      RECT 0.280 49.280 208.720 49.840 ;
      RECT 0.280 53.760 208.720 54.320 ;
      RECT 0.280 58.240 208.720 58.800 ;
      RECT 0.280 62.720 208.720 63.280 ;
      RECT 0.280 67.200 208.720 67.760 ;
      RECT 0.280 71.680 208.720 72.240 ;
      RECT 0.280 76.160 208.720 76.720 ;
      RECT 0.280 80.640 208.720 81.200 ;
      RECT 0.280 85.120 208.720 85.680 ;
      RECT 0.280 89.600 208.720 90.160 ;
      RECT 0.280 94.080 208.720 94.640 ;
      RECT 0.280 98.560 208.720 99.120 ;
      RECT 0.280 103.040 208.720 103.600 ;
      RECT 0.280 107.520 208.720 108.080 ;
      RECT 0.280 112.000 208.720 112.560 ;
      RECT 0.280 116.480 208.720 117.040 ;
      RECT 0.280 120.960 208.720 121.520 ;
      RECT 0.280 125.440 208.720 126.000 ;
      RECT 0.280 129.920 208.720 130.480 ;
      RECT 0.280 134.400 208.720 134.960 ;
      RECT 0.280 138.880 208.720 139.440 ;
      RECT 0.280 143.360 208.720 143.920 ;
      RECT 0.280 147.840 208.720 148.400 ;
      RECT 0.280 152.320 208.720 152.880 ;
      RECT 0.280 156.800 208.720 157.360 ;
      RECT 0.280 161.280 208.720 161.840 ;
      RECT 0.280 165.760 208.720 166.320 ;
      RECT 0.280 170.240 208.720 170.800 ;
      RECT 0.280 174.720 208.720 175.280 ;
      RECT 0.280 179.200 208.720 179.760 ;
      RECT 0.280 183.680 208.720 184.240 ;
      RECT 0.280 188.160 208.720 188.720 ;
      RECT 0.280 192.640 208.720 193.200 ;
      RECT 0.280 197.120 208.720 197.680 ;
      RECT 0.280 201.600 208.720 202.160 ;
      RECT 0.280 206.080 208.720 206.640 ;
      RECT 0.280 210.560 208.720 211.120 ;
      RECT 0.280 215.040 208.720 215.600 ;
      RECT 0.280 219.520 208.720 220.080 ;
      RECT 0.280 224.000 208.720 224.560 ;
      RECT 0.280 228.480 208.720 229.040 ;
      RECT 0.280 232.960 208.720 233.520 ;
      RECT 0.280 237.440 208.720 238.000 ;
      RECT 0.280 241.920 208.720 242.480 ;
      RECT 0.280 246.400 208.720 246.960 ;
      RECT 0.280 250.880 208.720 251.440 ;
      RECT 0.280 255.360 208.720 255.920 ;
      RECT 0.280 259.840 208.720 260.400 ;
      RECT 0.280 264.320 208.720 264.880 ;
      RECT 0.280 268.800 208.720 269.360 ;
      RECT 0.280 273.280 208.720 273.840 ;
      RECT 0.280 277.760 208.720 278.320 ;
      RECT 0.280 282.240 208.720 282.800 ;
      RECT 0.280 286.720 208.720 287.280 ;
      RECT 0.280 291.200 208.720 291.760 ;
      RECT 0.280 295.680 208.720 296.240 ;
      RECT 0.280 300.160 208.720 300.720 ;
      RECT 0.280 304.640 208.720 305.200 ;
      RECT 0.280 309.120 208.720 309.680 ;
      RECT 0.280 313.600 208.720 314.160 ;
      RECT 0.280 318.080 208.720 318.640 ;
      RECT 0.280 322.560 208.720 323.120 ;
      RECT 0.280 327.040 208.720 327.600 ;
      RECT 0.280 331.520 208.720 332.080 ;
      RECT 0.280 336.000 208.720 336.560 ;
      RECT 0.280 340.480 208.720 341.040 ;
      RECT 0.280 344.960 208.720 345.520 ;
      RECT 0.280 349.440 208.720 350.000 ;
      RECT 0.280 353.920 208.720 354.480 ;
      RECT 0.280 358.400 208.720 358.960 ;
      RECT 0.280 362.880 208.720 363.440 ;
      RECT 0.280 367.360 208.720 367.920 ;
      RECT 0.280 371.840 208.720 372.400 ;
      RECT 0.280 376.320 208.720 376.880 ;
      RECT 0.280 380.800 208.720 381.360 ;
      RECT 0.280 385.280 208.720 385.840 ;
      RECT 0.280 389.760 208.720 390.320 ;
      RECT 0.280 394.240 208.720 394.800 ;
      RECT 0.280 398.720 208.720 399.280 ;
      RECT 0.280 403.200 208.720 403.760 ;
      RECT 0.280 407.680 208.720 408.240 ;
      RECT 0.280 412.160 208.720 412.720 ;
      RECT 0.280 416.640 208.720 417.200 ;
      RECT 0.280 421.120 208.720 421.680 ;
      RECT 0.280 425.600 208.720 426.160 ;
      RECT 0.280 430.080 208.720 430.640 ;
      RECT 0.280 434.560 208.720 435.120 ;
      RECT 0.280 439.040 208.720 439.600 ;
      RECT 0.280 443.520 208.720 444.080 ;
      RECT 0.280 448.000 208.720 448.560 ;
      RECT 0.280 452.480 208.720 453.040 ;
      RECT 0.280 456.960 208.720 457.520 ;
      RECT 0.280 461.440 208.720 462.000 ;
      RECT 0.280 465.920 208.720 466.480 ;
      RECT 0.280 470.400 208.720 470.960 ;
      RECT 0.280 474.880 208.720 475.440 ;
      RECT 0.280 479.360 208.720 479.920 ;
      RECT 0.280 483.840 208.720 484.400 ;
      RECT 0.280 488.320 208.720 488.880 ;
      RECT 0.280 492.800 208.720 493.360 ;
      RECT 0.280 497.280 208.720 497.840 ;
      RECT 0.280 501.760 208.720 502.320 ;
      RECT 0.280 506.240 208.720 506.800 ;
      RECT 0.280 510.720 208.720 511.280 ;
      RECT 0.280 515.200 208.720 515.760 ;
      RECT 0.280 519.680 208.720 520.240 ;
      RECT 0.280 524.160 208.720 524.720 ;
      RECT 0.280 528.640 208.720 529.200 ;
      RECT 0.280 533.120 208.720 533.680 ;
      RECT 0.280 537.600 208.720 538.160 ;
      RECT 0.280 542.080 208.720 542.640 ;
      RECT 0.280 546.560 208.720 547.120 ;
      RECT 0.280 551.040 208.720 551.600 ;
      RECT 0.280 555.520 208.720 556.080 ;
      RECT 0.280 560.000 208.720 560.560 ;
      RECT 0.280 564.480 208.720 565.040 ;
      RECT 0.280 568.960 208.720 569.520 ;
      RECT 0.280 573.440 208.720 574.000 ;
      RECT 0.280 577.920 208.720 578.480 ;
      RECT 0.280 582.400 208.720 582.960 ;
      RECT 0.280 586.880 208.720 587.440 ;
      RECT 0.280 591.360 208.720 591.920 ;
      RECT 0.280 595.840 208.720 596.400 ;
      RECT 0.280 600.320 208.720 600.880 ;
      RECT 0.280 604.800 208.720 605.360 ;
      RECT 0.280 609.280 208.720 609.840 ;
      RECT 0.280 613.760 208.720 614.320 ;
      RECT 0.280 618.240 208.720 618.800 ;
      RECT 0.280 622.720 208.720 623.280 ;
      RECT 0.280 627.200 208.720 627.760 ;
      RECT 0.280 631.680 208.720 632.240 ;
      RECT 0.280 636.160 208.720 636.720 ;
      RECT 0.280 640.640 208.720 641.200 ;
      RECT 0.280 645.120 208.720 645.680 ;
      RECT 0.280 649.600 208.720 650.160 ;
      RECT 0.280 654.080 208.720 654.640 ;
      RECT 0.280 658.560 208.720 659.120 ;
      RECT 0.280 663.040 208.720 663.600 ;
      RECT 0.280 667.520 208.720 668.080 ;
      RECT 0.280 672.000 208.720 672.560 ;
      RECT 0.280 676.480 208.720 677.040 ;
      RECT 0.280 680.960 208.720 681.520 ;
      RECT 0.280 685.440 208.720 686.000 ;
      RECT 0.280 689.920 208.720 690.480 ;
      RECT 0.280 694.400 208.720 694.960 ;
      RECT 0.280 698.880 208.720 699.440 ;
      RECT 0.280 703.360 208.720 703.920 ;
      RECT 0.280 707.840 208.720 708.400 ;
      RECT 0.280 712.320 208.720 712.880 ;
      RECT 0.280 716.800 208.720 717.360 ;
      RECT 0.280 721.280 208.720 721.840 ;
      RECT 0.280 725.760 208.720 726.320 ;
      RECT 0.280 730.240 208.720 730.800 ;
      RECT 0.280 734.720 208.720 735.280 ;
      RECT 0.280 739.200 208.720 739.760 ;
      RECT 0.280 743.680 208.720 744.240 ;
      RECT 0.280 748.160 208.720 748.720 ;
      RECT 0.280 752.640 208.720 753.200 ;
      RECT 0.280 757.120 208.720 757.680 ;
      RECT 0.280 761.600 208.720 762.160 ;
      RECT 0.280 766.080 208.720 766.640 ;
      RECT 0.280 770.560 208.720 771.120 ;
      RECT 0.280 775.040 208.720 775.600 ;
      RECT 0.280 779.520 208.720 780.080 ;
      RECT 0.280 784.000 208.720 784.560 ;
      RECT 0.280 788.480 208.720 789.040 ;
      RECT 0.280 792.960 208.720 793.520 ;
      RECT 0.280 797.440 208.720 798.000 ;
      RECT 0.280 801.920 208.720 802.480 ;
      RECT 0.280 806.400 208.720 806.960 ;
      RECT 0.280 810.880 208.720 811.440 ;
      RECT 0.280 815.360 208.720 815.920 ;
      RECT 0.280 819.840 208.720 820.400 ;
      RECT 0.280 824.320 208.720 824.880 ;
      RECT 0.280 828.800 208.720 829.360 ;
      RECT 0.280 833.280 208.720 833.840 ;
      RECT 0.280 837.760 208.720 838.320 ;
      RECT 0.280 842.240 208.720 842.800 ;
      RECT 0.280 846.720 208.720 847.280 ;
      RECT 0.280 851.200 208.720 851.760 ;
      RECT 0.280 855.680 208.720 856.240 ;
      RECT 0.280 860.160 208.720 860.720 ;
      RECT 0.280 864.640 208.720 865.200 ;
      RECT 0.280 869.120 208.720 869.680 ;
      RECT 0.280 873.600 208.720 874.160 ;
      RECT 0.280 878.080 208.720 878.640 ;
      RECT 0.280 882.560 208.720 883.120 ;
      RECT 0.280 887.040 208.720 887.600 ;
      RECT 0.280 891.520 208.720 892.080 ;
      RECT 0.280 896.000 208.720 896.560 ;
      RECT 0.280 900.480 208.720 901.040 ;
      RECT 0.280 904.960 208.720 905.520 ;
      RECT 0.280 909.440 208.720 910.000 ;
      RECT 0.280 913.920 208.720 914.480 ;
      RECT 0.280 918.400 208.720 918.960 ;
      RECT 0.280 922.880 208.720 923.440 ;
      RECT 0.280 927.360 208.720 927.920 ;
      RECT 0.280 931.840 208.720 932.400 ;
      RECT 0.280 936.320 208.720 936.880 ;
      RECT 0.280 940.800 208.720 941.360 ;
      RECT 0.280 945.280 208.720 945.840 ;
      RECT 0.280 949.760 208.720 950.320 ;
      RECT 0.280 954.240 208.720 954.800 ;
      RECT 0.280 958.720 208.720 959.280 ;
      RECT 0.280 963.200 208.720 963.760 ;
      RECT 0.280 967.680 208.720 968.240 ;
      RECT 0.280 972.160 208.720 972.720 ;
      RECT 0.280 976.640 208.720 977.200 ;
      RECT 0.280 981.120 208.720 981.680 ;
      RECT 0.280 985.600 208.720 986.160 ;
      RECT 0.280 990.080 208.720 990.640 ;
      RECT 0.280 994.560 208.720 995.120 ;
      RECT 0.280 999.040 208.720 999.600 ;
      RECT 0.280 1003.520 208.720 1004.080 ;
      RECT 0.280 1008.000 208.720 1008.560 ;
      RECT 0.280 1012.480 208.720 1013.040 ;
      RECT 0.280 1016.960 208.720 1017.520 ;
      RECT 0.280 1021.440 208.720 1022.000 ;
      RECT 0.280 1025.920 208.720 1026.480 ;
      RECT 0.280 1030.400 208.720 1030.960 ;
      RECT 0.280 1034.880 208.720 1035.440 ;
      RECT 0.280 1039.360 208.720 1039.920 ;
      RECT 0.280 1043.840 208.720 1044.400 ;
      RECT 0.280 1048.320 208.720 1048.880 ;
      RECT 0.280 1052.800 208.720 1053.360 ;
      RECT 0.280 1057.280 208.720 1057.840 ;
      RECT 0.280 1061.760 208.720 1062.320 ;
      RECT 0.280 1066.240 208.720 1066.800 ;
      RECT 0.280 1070.720 208.720 1071.280 ;
      RECT 0.280 1075.200 208.720 1075.760 ;
      RECT 0.280 1079.680 208.720 1080.240 ;
      RECT 0.280 1084.160 208.720 1084.720 ;
      RECT 0.280 1088.640 208.720 1089.200 ;
      RECT 0.280 1093.120 208.720 1093.680 ;
      RECT 0.280 1097.600 208.720 1098.160 ;
      RECT 0.280 1102.080 208.720 1102.640 ;
      RECT 0.280 1106.560 208.720 1107.120 ;
      RECT 0.280 1111.040 208.720 1111.600 ;
      RECT 0.280 1115.520 208.720 1116.080 ;
      RECT 0.280 1120.000 208.720 1120.560 ;
      RECT 0.280 1124.480 208.720 1125.040 ;
      RECT 0.280 1128.960 208.720 1129.520 ;
      RECT 0.280 1133.440 208.720 1134.000 ;
      RECT 0.280 1137.920 208.720 1138.480 ;
      RECT 0.280 1142.400 208.720 1142.960 ;
      RECT 0.280 1146.880 208.720 1147.440 ;
      RECT 0.280 1151.360 208.720 1151.920 ;
      RECT 0.280 1155.840 208.720 1156.400 ;
      RECT 0.280 1160.320 208.720 1160.880 ;
      RECT 0.280 1164.800 208.720 1165.360 ;
      RECT 0.280 1169.280 208.720 1169.840 ;
      RECT 0.280 1173.760 208.720 1174.320 ;
      RECT 0.280 1178.240 208.720 1178.800 ;
      RECT 0.280 1182.720 208.720 1183.280 ;
      RECT 0.280 1187.200 208.720 1187.760 ;
      RECT 0.280 1191.680 208.720 1192.240 ;
      RECT 0.280 1196.160 208.720 1196.720 ;
      RECT 0.280 1200.640 208.720 1201.200 ;
      RECT 0.280 1205.120 208.720 1205.680 ;
      RECT 0.280 1209.600 208.720 1210.160 ;
      RECT 0.280 1214.080 208.720 1214.640 ;
      RECT 0.280 1218.560 208.720 1219.120 ;
      RECT 0.280 1223.040 208.720 1223.600 ;
      RECT 0.280 1227.520 208.720 1228.080 ;
    END
  END VSS
  PIN VDD
    DIRECTION INOUT ;
    USE POWER ;
    PORT
      LAYER metal4_bottom_tier ;
      RECT 0.280 2.240 208.720 2.800 ;
      RECT 0.280 6.720 208.720 7.280 ;
      RECT 0.280 11.200 208.720 11.760 ;
      RECT 0.280 15.680 208.720 16.240 ;
      RECT 0.280 20.160 208.720 20.720 ;
      RECT 0.280 24.640 208.720 25.200 ;
      RECT 0.280 29.120 208.720 29.680 ;
      RECT 0.280 33.600 208.720 34.160 ;
      RECT 0.280 38.080 208.720 38.640 ;
      RECT 0.280 42.560 208.720 43.120 ;
      RECT 0.280 47.040 208.720 47.600 ;
      RECT 0.280 51.520 208.720 52.080 ;
      RECT 0.280 56.000 208.720 56.560 ;
      RECT 0.280 60.480 208.720 61.040 ;
      RECT 0.280 64.960 208.720 65.520 ;
      RECT 0.280 69.440 208.720 70.000 ;
      RECT 0.280 73.920 208.720 74.480 ;
      RECT 0.280 78.400 208.720 78.960 ;
      RECT 0.280 82.880 208.720 83.440 ;
      RECT 0.280 87.360 208.720 87.920 ;
      RECT 0.280 91.840 208.720 92.400 ;
      RECT 0.280 96.320 208.720 96.880 ;
      RECT 0.280 100.800 208.720 101.360 ;
      RECT 0.280 105.280 208.720 105.840 ;
      RECT 0.280 109.760 208.720 110.320 ;
      RECT 0.280 114.240 208.720 114.800 ;
      RECT 0.280 118.720 208.720 119.280 ;
      RECT 0.280 123.200 208.720 123.760 ;
      RECT 0.280 127.680 208.720 128.240 ;
      RECT 0.280 132.160 208.720 132.720 ;
      RECT 0.280 136.640 208.720 137.200 ;
      RECT 0.280 141.120 208.720 141.680 ;
      RECT 0.280 145.600 208.720 146.160 ;
      RECT 0.280 150.080 208.720 150.640 ;
      RECT 0.280 154.560 208.720 155.120 ;
      RECT 0.280 159.040 208.720 159.600 ;
      RECT 0.280 163.520 208.720 164.080 ;
      RECT 0.280 168.000 208.720 168.560 ;
      RECT 0.280 172.480 208.720 173.040 ;
      RECT 0.280 176.960 208.720 177.520 ;
      RECT 0.280 181.440 208.720 182.000 ;
      RECT 0.280 185.920 208.720 186.480 ;
      RECT 0.280 190.400 208.720 190.960 ;
      RECT 0.280 194.880 208.720 195.440 ;
      RECT 0.280 199.360 208.720 199.920 ;
      RECT 0.280 203.840 208.720 204.400 ;
      RECT 0.280 208.320 208.720 208.880 ;
      RECT 0.280 212.800 208.720 213.360 ;
      RECT 0.280 217.280 208.720 217.840 ;
      RECT 0.280 221.760 208.720 222.320 ;
      RECT 0.280 226.240 208.720 226.800 ;
      RECT 0.280 230.720 208.720 231.280 ;
      RECT 0.280 235.200 208.720 235.760 ;
      RECT 0.280 239.680 208.720 240.240 ;
      RECT 0.280 244.160 208.720 244.720 ;
      RECT 0.280 248.640 208.720 249.200 ;
      RECT 0.280 253.120 208.720 253.680 ;
      RECT 0.280 257.600 208.720 258.160 ;
      RECT 0.280 262.080 208.720 262.640 ;
      RECT 0.280 266.560 208.720 267.120 ;
      RECT 0.280 271.040 208.720 271.600 ;
      RECT 0.280 275.520 208.720 276.080 ;
      RECT 0.280 280.000 208.720 280.560 ;
      RECT 0.280 284.480 208.720 285.040 ;
      RECT 0.280 288.960 208.720 289.520 ;
      RECT 0.280 293.440 208.720 294.000 ;
      RECT 0.280 297.920 208.720 298.480 ;
      RECT 0.280 302.400 208.720 302.960 ;
      RECT 0.280 306.880 208.720 307.440 ;
      RECT 0.280 311.360 208.720 311.920 ;
      RECT 0.280 315.840 208.720 316.400 ;
      RECT 0.280 320.320 208.720 320.880 ;
      RECT 0.280 324.800 208.720 325.360 ;
      RECT 0.280 329.280 208.720 329.840 ;
      RECT 0.280 333.760 208.720 334.320 ;
      RECT 0.280 338.240 208.720 338.800 ;
      RECT 0.280 342.720 208.720 343.280 ;
      RECT 0.280 347.200 208.720 347.760 ;
      RECT 0.280 351.680 208.720 352.240 ;
      RECT 0.280 356.160 208.720 356.720 ;
      RECT 0.280 360.640 208.720 361.200 ;
      RECT 0.280 365.120 208.720 365.680 ;
      RECT 0.280 369.600 208.720 370.160 ;
      RECT 0.280 374.080 208.720 374.640 ;
      RECT 0.280 378.560 208.720 379.120 ;
      RECT 0.280 383.040 208.720 383.600 ;
      RECT 0.280 387.520 208.720 388.080 ;
      RECT 0.280 392.000 208.720 392.560 ;
      RECT 0.280 396.480 208.720 397.040 ;
      RECT 0.280 400.960 208.720 401.520 ;
      RECT 0.280 405.440 208.720 406.000 ;
      RECT 0.280 409.920 208.720 410.480 ;
      RECT 0.280 414.400 208.720 414.960 ;
      RECT 0.280 418.880 208.720 419.440 ;
      RECT 0.280 423.360 208.720 423.920 ;
      RECT 0.280 427.840 208.720 428.400 ;
      RECT 0.280 432.320 208.720 432.880 ;
      RECT 0.280 436.800 208.720 437.360 ;
      RECT 0.280 441.280 208.720 441.840 ;
      RECT 0.280 445.760 208.720 446.320 ;
      RECT 0.280 450.240 208.720 450.800 ;
      RECT 0.280 454.720 208.720 455.280 ;
      RECT 0.280 459.200 208.720 459.760 ;
      RECT 0.280 463.680 208.720 464.240 ;
      RECT 0.280 468.160 208.720 468.720 ;
      RECT 0.280 472.640 208.720 473.200 ;
      RECT 0.280 477.120 208.720 477.680 ;
      RECT 0.280 481.600 208.720 482.160 ;
      RECT 0.280 486.080 208.720 486.640 ;
      RECT 0.280 490.560 208.720 491.120 ;
      RECT 0.280 495.040 208.720 495.600 ;
      RECT 0.280 499.520 208.720 500.080 ;
      RECT 0.280 504.000 208.720 504.560 ;
      RECT 0.280 508.480 208.720 509.040 ;
      RECT 0.280 512.960 208.720 513.520 ;
      RECT 0.280 517.440 208.720 518.000 ;
      RECT 0.280 521.920 208.720 522.480 ;
      RECT 0.280 526.400 208.720 526.960 ;
      RECT 0.280 530.880 208.720 531.440 ;
      RECT 0.280 535.360 208.720 535.920 ;
      RECT 0.280 539.840 208.720 540.400 ;
      RECT 0.280 544.320 208.720 544.880 ;
      RECT 0.280 548.800 208.720 549.360 ;
      RECT 0.280 553.280 208.720 553.840 ;
      RECT 0.280 557.760 208.720 558.320 ;
      RECT 0.280 562.240 208.720 562.800 ;
      RECT 0.280 566.720 208.720 567.280 ;
      RECT 0.280 571.200 208.720 571.760 ;
      RECT 0.280 575.680 208.720 576.240 ;
      RECT 0.280 580.160 208.720 580.720 ;
      RECT 0.280 584.640 208.720 585.200 ;
      RECT 0.280 589.120 208.720 589.680 ;
      RECT 0.280 593.600 208.720 594.160 ;
      RECT 0.280 598.080 208.720 598.640 ;
      RECT 0.280 602.560 208.720 603.120 ;
      RECT 0.280 607.040 208.720 607.600 ;
      RECT 0.280 611.520 208.720 612.080 ;
      RECT 0.280 616.000 208.720 616.560 ;
      RECT 0.280 620.480 208.720 621.040 ;
      RECT 0.280 624.960 208.720 625.520 ;
      RECT 0.280 629.440 208.720 630.000 ;
      RECT 0.280 633.920 208.720 634.480 ;
      RECT 0.280 638.400 208.720 638.960 ;
      RECT 0.280 642.880 208.720 643.440 ;
      RECT 0.280 647.360 208.720 647.920 ;
      RECT 0.280 651.840 208.720 652.400 ;
      RECT 0.280 656.320 208.720 656.880 ;
      RECT 0.280 660.800 208.720 661.360 ;
      RECT 0.280 665.280 208.720 665.840 ;
      RECT 0.280 669.760 208.720 670.320 ;
      RECT 0.280 674.240 208.720 674.800 ;
      RECT 0.280 678.720 208.720 679.280 ;
      RECT 0.280 683.200 208.720 683.760 ;
      RECT 0.280 687.680 208.720 688.240 ;
      RECT 0.280 692.160 208.720 692.720 ;
      RECT 0.280 696.640 208.720 697.200 ;
      RECT 0.280 701.120 208.720 701.680 ;
      RECT 0.280 705.600 208.720 706.160 ;
      RECT 0.280 710.080 208.720 710.640 ;
      RECT 0.280 714.560 208.720 715.120 ;
      RECT 0.280 719.040 208.720 719.600 ;
      RECT 0.280 723.520 208.720 724.080 ;
      RECT 0.280 728.000 208.720 728.560 ;
      RECT 0.280 732.480 208.720 733.040 ;
      RECT 0.280 736.960 208.720 737.520 ;
      RECT 0.280 741.440 208.720 742.000 ;
      RECT 0.280 745.920 208.720 746.480 ;
      RECT 0.280 750.400 208.720 750.960 ;
      RECT 0.280 754.880 208.720 755.440 ;
      RECT 0.280 759.360 208.720 759.920 ;
      RECT 0.280 763.840 208.720 764.400 ;
      RECT 0.280 768.320 208.720 768.880 ;
      RECT 0.280 772.800 208.720 773.360 ;
      RECT 0.280 777.280 208.720 777.840 ;
      RECT 0.280 781.760 208.720 782.320 ;
      RECT 0.280 786.240 208.720 786.800 ;
      RECT 0.280 790.720 208.720 791.280 ;
      RECT 0.280 795.200 208.720 795.760 ;
      RECT 0.280 799.680 208.720 800.240 ;
      RECT 0.280 804.160 208.720 804.720 ;
      RECT 0.280 808.640 208.720 809.200 ;
      RECT 0.280 813.120 208.720 813.680 ;
      RECT 0.280 817.600 208.720 818.160 ;
      RECT 0.280 822.080 208.720 822.640 ;
      RECT 0.280 826.560 208.720 827.120 ;
      RECT 0.280 831.040 208.720 831.600 ;
      RECT 0.280 835.520 208.720 836.080 ;
      RECT 0.280 840.000 208.720 840.560 ;
      RECT 0.280 844.480 208.720 845.040 ;
      RECT 0.280 848.960 208.720 849.520 ;
      RECT 0.280 853.440 208.720 854.000 ;
      RECT 0.280 857.920 208.720 858.480 ;
      RECT 0.280 862.400 208.720 862.960 ;
      RECT 0.280 866.880 208.720 867.440 ;
      RECT 0.280 871.360 208.720 871.920 ;
      RECT 0.280 875.840 208.720 876.400 ;
      RECT 0.280 880.320 208.720 880.880 ;
      RECT 0.280 884.800 208.720 885.360 ;
      RECT 0.280 889.280 208.720 889.840 ;
      RECT 0.280 893.760 208.720 894.320 ;
      RECT 0.280 898.240 208.720 898.800 ;
      RECT 0.280 902.720 208.720 903.280 ;
      RECT 0.280 907.200 208.720 907.760 ;
      RECT 0.280 911.680 208.720 912.240 ;
      RECT 0.280 916.160 208.720 916.720 ;
      RECT 0.280 920.640 208.720 921.200 ;
      RECT 0.280 925.120 208.720 925.680 ;
      RECT 0.280 929.600 208.720 930.160 ;
      RECT 0.280 934.080 208.720 934.640 ;
      RECT 0.280 938.560 208.720 939.120 ;
      RECT 0.280 943.040 208.720 943.600 ;
      RECT 0.280 947.520 208.720 948.080 ;
      RECT 0.280 952.000 208.720 952.560 ;
      RECT 0.280 956.480 208.720 957.040 ;
      RECT 0.280 960.960 208.720 961.520 ;
      RECT 0.280 965.440 208.720 966.000 ;
      RECT 0.280 969.920 208.720 970.480 ;
      RECT 0.280 974.400 208.720 974.960 ;
      RECT 0.280 978.880 208.720 979.440 ;
      RECT 0.280 983.360 208.720 983.920 ;
      RECT 0.280 987.840 208.720 988.400 ;
      RECT 0.280 992.320 208.720 992.880 ;
      RECT 0.280 996.800 208.720 997.360 ;
      RECT 0.280 1001.280 208.720 1001.840 ;
      RECT 0.280 1005.760 208.720 1006.320 ;
      RECT 0.280 1010.240 208.720 1010.800 ;
      RECT 0.280 1014.720 208.720 1015.280 ;
      RECT 0.280 1019.200 208.720 1019.760 ;
      RECT 0.280 1023.680 208.720 1024.240 ;
      RECT 0.280 1028.160 208.720 1028.720 ;
      RECT 0.280 1032.640 208.720 1033.200 ;
      RECT 0.280 1037.120 208.720 1037.680 ;
      RECT 0.280 1041.600 208.720 1042.160 ;
      RECT 0.280 1046.080 208.720 1046.640 ;
      RECT 0.280 1050.560 208.720 1051.120 ;
      RECT 0.280 1055.040 208.720 1055.600 ;
      RECT 0.280 1059.520 208.720 1060.080 ;
      RECT 0.280 1064.000 208.720 1064.560 ;
      RECT 0.280 1068.480 208.720 1069.040 ;
      RECT 0.280 1072.960 208.720 1073.520 ;
      RECT 0.280 1077.440 208.720 1078.000 ;
      RECT 0.280 1081.920 208.720 1082.480 ;
      RECT 0.280 1086.400 208.720 1086.960 ;
      RECT 0.280 1090.880 208.720 1091.440 ;
      RECT 0.280 1095.360 208.720 1095.920 ;
      RECT 0.280 1099.840 208.720 1100.400 ;
      RECT 0.280 1104.320 208.720 1104.880 ;
      RECT 0.280 1108.800 208.720 1109.360 ;
      RECT 0.280 1113.280 208.720 1113.840 ;
      RECT 0.280 1117.760 208.720 1118.320 ;
      RECT 0.280 1122.240 208.720 1122.800 ;
      RECT 0.280 1126.720 208.720 1127.280 ;
      RECT 0.280 1131.200 208.720 1131.760 ;
      RECT 0.280 1135.680 208.720 1136.240 ;
      RECT 0.280 1140.160 208.720 1140.720 ;
      RECT 0.280 1144.640 208.720 1145.200 ;
      RECT 0.280 1149.120 208.720 1149.680 ;
      RECT 0.280 1153.600 208.720 1154.160 ;
      RECT 0.280 1158.080 208.720 1158.640 ;
      RECT 0.280 1162.560 208.720 1163.120 ;
      RECT 0.280 1167.040 208.720 1167.600 ;
      RECT 0.280 1171.520 208.720 1172.080 ;
      RECT 0.280 1176.000 208.720 1176.560 ;
      RECT 0.280 1180.480 208.720 1181.040 ;
      RECT 0.280 1184.960 208.720 1185.520 ;
      RECT 0.280 1189.440 208.720 1190.000 ;
      RECT 0.280 1193.920 208.720 1194.480 ;
      RECT 0.280 1198.400 208.720 1198.960 ;
      RECT 0.280 1202.880 208.720 1203.440 ;
      RECT 0.280 1207.360 208.720 1207.920 ;
      RECT 0.280 1211.840 208.720 1212.400 ;
      RECT 0.280 1216.320 208.720 1216.880 ;
      RECT 0.280 1220.800 208.720 1221.360 ;
      RECT 0.280 1225.280 208.720 1225.840 ;
    END
  END VDD
  OBS
    LAYER metal1_bottom_tier ;
    RECT 0 0 209.000 1229.200 ;
    LAYER metal2_bottom_tier ;
    RECT 0 0 209.000 1229.200 ;
    LAYER metal3_bottom_tier ;
    RECT 0 0 209.000 1229.200 ;
    LAYER metal4_bottom_tier ;
    RECT 0 0 209.000 1229.200 ;
  END
END fakeram45_8192x64_bottom_tier

END LIBRARY
